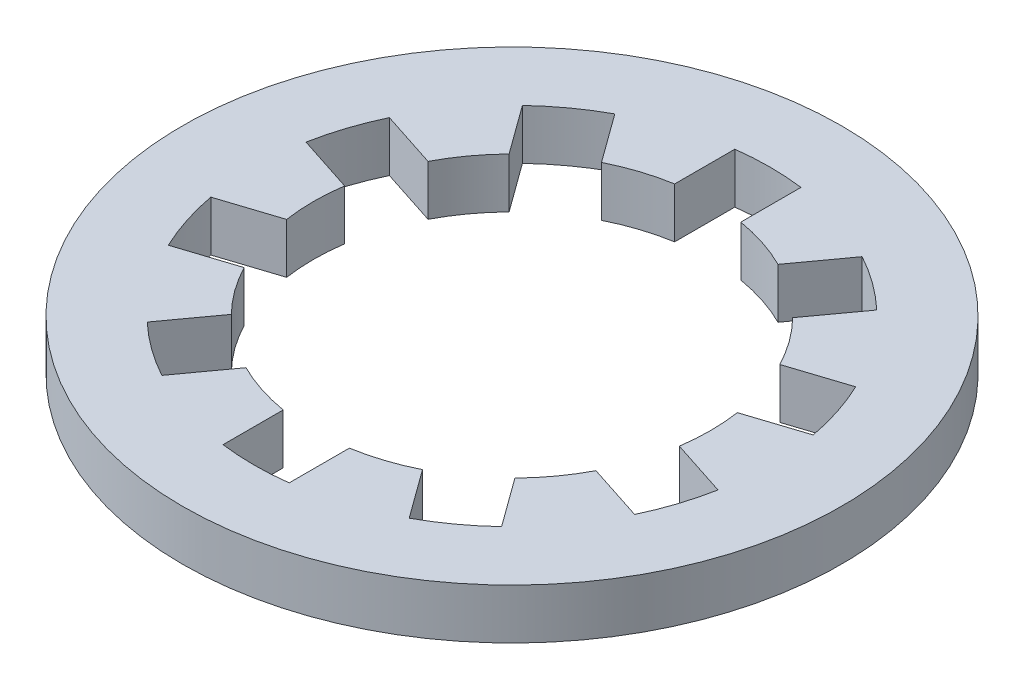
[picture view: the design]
ISO-10303-21;
HEADER;
FILE_DESCRIPTION(('STEP AP214'),'2;1');
FILE_NAME('part.step','',(''),(''),'','','');
FILE_SCHEMA(('AUTOMOTIVE_DESIGN { 1 0 10303 214 1 1 1 1 }'));
ENDSEC;
DATA;
#1=APPLICATION_CONTEXT('core data for automotive mechanical design processes');
#2=APPLICATION_PROTOCOL_DEFINITION('international standard','automotive_design',2000,#1);
#3=PRODUCT_CONTEXT('',#1,'mechanical');
#4=PRODUCT('Part','Part','',(#3));
#5=PRODUCT_RELATED_PRODUCT_CATEGORY('part','',(#4));
#6=PRODUCT_DEFINITION_FORMATION('','',#4);
#7=PRODUCT_DEFINITION_CONTEXT('part definition',#1,'design');
#8=PRODUCT_DEFINITION('design','',#6,#7);
#9=PRODUCT_DEFINITION_SHAPE('','',#8);
#10=(LENGTH_UNIT() NAMED_UNIT(*) SI_UNIT(.MILLI.,.METRE.));
#11=(NAMED_UNIT(*) PLANE_ANGLE_UNIT() SI_UNIT($,.RADIAN.));
#12=(NAMED_UNIT(*) SI_UNIT($,.STERADIAN.) SOLID_ANGLE_UNIT());
#13=UNCERTAINTY_MEASURE_WITH_UNIT(LENGTH_MEASURE(1.E-05),#10,'distance_accuracy_value','');
#14=(GEOMETRIC_REPRESENTATION_CONTEXT(3) GLOBAL_UNCERTAINTY_ASSIGNED_CONTEXT((#13)) GLOBAL_UNIT_ASSIGNED_CONTEXT((#10,
#11,#12)) REPRESENTATION_CONTEXT('',''));
#15=CARTESIAN_POINT('',(0.,0.,0.));
#16=DIRECTION('',(0.,0.,1.));
#17=DIRECTION('',(1.,0.,0.));
#18=AXIS2_PLACEMENT_3D('',#15,#16,#17);
#19=CARTESIAN_POINT('',(0.,1.7018,0.));
#20=DIRECTION('',(0.,-1.,0.));
#21=DIRECTION('',(0.,0.,-1.));
#22=AXIS2_PLACEMENT_3D('',#19,#20,#21);
#23=CYLINDRICAL_SURFACE('',#22,6.731);
#24=DIRECTION('',(0.,1.,0.));
#25=VECTOR('',#24,1.);
#26=CARTESIAN_POINT('',(-4.80862801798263,0.,4.70993180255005));
#27=LINE('',#26,#25);
#28=CARTESIAN_POINT('',(-4.80862801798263,0.,4.70993180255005));
#29=VERTEX_POINT('',#28);
#30=CARTESIAN_POINT('',(-4.80862801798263,1.7018,4.70993180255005));
#31=VERTEX_POINT('',#30);
#32=EDGE_CURVE('E322',#29,#31,#27,.T.);
#33=ORIENTED_EDGE('',*,*,#32,.F.);
#34=CARTESIAN_POINT('',(0.,0.,0.));
#35=DIRECTION('',(0.,1.,0.));
#36=DIRECTION('',(0.,0.,1.));
#37=AXIS2_PLACEMENT_3D('',#34,#35,#36);
#38=CIRCLE('',#37,6.731);
#39=CARTESIAN_POINT('',(-5.96535910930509,0.,3.11782804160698));
#40=VERTEX_POINT('',#39);
#41=EDGE_CURVE('E570',#40,#29,#38,.T.);
#42=ORIENTED_EDGE('',*,*,#41,.F.);
#43=DIRECTION('',(0.,1.,0.));
#44=VECTOR('',#43,1.);
#45=CARTESIAN_POINT('',(-5.96535910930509,0.,3.11782804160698));
#46=LINE('',#45,#44);
#47=CARTESIAN_POINT('',(-5.96535910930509,1.7018,3.11782804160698));
#48=VERTEX_POINT('',#47);
#49=EDGE_CURVE('E346',#40,#48,#46,.T.);
#50=ORIENTED_EDGE('',*,*,#49,.T.);
#51=CARTESIAN_POINT('',(0.,1.7018,0.));
#52=DIRECTION('',(0.,1.,0.));
#53=DIRECTION('',(0.,0.,1.));
#54=AXIS2_PLACEMENT_3D('',#51,#52,#53);
#55=CIRCLE('',#54,6.731);
#56=EDGE_CURVE('E567',#48,#31,#55,.T.);
#57=ORIENTED_EDGE('',*,*,#56,.T.);
#58=EDGE_LOOP('',(#33,#42,#50,#57));
#59=FACE_BOUND('',#58,.T.);
#60=ADVANCED_FACE('F35',(#59),#23,.F.);
#61=DIRECTION('',(0.,1.,0.));
#62=VECTOR('',#61,1.);
#63=CARTESIAN_POINT('',(-6.6586902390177,0.,0.983974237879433));
#64=LINE('',#63,#62);
#65=CARTESIAN_POINT('',(-6.6586902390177,0.,0.983974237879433));
#66=VERTEX_POINT('',#65);
#67=CARTESIAN_POINT('',(-6.6586902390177,1.7018,0.983974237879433));
#68=VERTEX_POINT('',#67);
#69=EDGE_CURVE('E344',#66,#68,#64,.T.);
#70=ORIENTED_EDGE('',*,*,#69,.F.);
#71=CARTESIAN_POINT('',(-6.65869023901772,0.,-0.983974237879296));
#72=VERTEX_POINT('',#71);
#73=EDGE_CURVE('E572',#72,#66,#38,.T.);
#74=ORIENTED_EDGE('',*,*,#73,.F.);
#75=DIRECTION('',(0.,1.,0.));
#76=VECTOR('',#75,1.);
#77=CARTESIAN_POINT('',(-6.65869023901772,0.,-0.983974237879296));
#78=LINE('',#77,#76);
#79=CARTESIAN_POINT('',(-6.65869023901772,1.7018,-0.983974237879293));
#80=VERTEX_POINT('',#79);
#81=EDGE_CURVE('E371',#72,#80,#78,.T.);
#82=ORIENTED_EDGE('',*,*,#81,.T.);
#83=EDGE_CURVE('E681',#80,#68,#55,.T.);
#84=ORIENTED_EDGE('',*,*,#83,.T.);
#85=EDGE_LOOP('',(#70,#74,#82,#84));
#86=FACE_BOUND('',#85,.T.);
#87=ADVANCED_FACE('F679',(#86),#23,.F.);
#88=DIRECTION('',(0.,1.,0.));
#89=VECTOR('',#88,1.);
#90=CARTESIAN_POINT('',(-5.96535910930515,0.,-3.11782804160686));
#91=LINE('',#90,#89);
#92=CARTESIAN_POINT('',(-5.96535910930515,0.,-3.11782804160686));
#93=VERTEX_POINT('',#92);
#94=CARTESIAN_POINT('',(-5.96535910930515,1.7018,-3.11782804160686));
#95=VERTEX_POINT('',#94);
#96=EDGE_CURVE('E369',#93,#95,#91,.T.);
#97=ORIENTED_EDGE('',*,*,#96,.F.);
#98=CARTESIAN_POINT('',(-4.80862801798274,0.,-4.70993180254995));
#99=VERTEX_POINT('',#98);
#100=EDGE_CURVE('E575',#99,#93,#38,.T.);
#101=ORIENTED_EDGE('',*,*,#100,.F.);
#102=DIRECTION('',(0.,1.,0.));
#103=VECTOR('',#102,1.);
#104=CARTESIAN_POINT('',(-4.80862801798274,0.,-4.70993180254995));
#105=LINE('',#104,#103);
#106=CARTESIAN_POINT('',(-4.80862801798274,1.7018,-4.70993180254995));
#107=VERTEX_POINT('',#106);
#108=EDGE_CURVE('E397',#99,#107,#105,.T.);
#109=ORIENTED_EDGE('',*,*,#108,.T.);
#110=EDGE_CURVE('E665',#107,#95,#55,.T.);
#111=ORIENTED_EDGE('',*,*,#110,.T.);
#112=EDGE_LOOP('',(#97,#101,#109,#111));
#113=FACE_BOUND('',#112,.T.);
#114=ADVANCED_FACE('F663',(#113),#23,.F.);
#115=DIRECTION('',(0.,1.,0.));
#116=VECTOR('',#115,1.);
#117=CARTESIAN_POINT('',(-2.99346355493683,0.,-6.02872598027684));
#118=LINE('',#117,#116);
#119=CARTESIAN_POINT('',(-2.99346355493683,0.,-6.02872598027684));
#120=VERTEX_POINT('',#119);
#121=CARTESIAN_POINT('',(-2.99346355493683,1.7018,-6.02872598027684));
#122=VERTEX_POINT('',#121);
#123=EDGE_CURVE('E395',#120,#122,#118,.T.);
#124=ORIENTED_EDGE('',*,*,#123,.F.);
#125=CARTESIAN_POINT('',(-1.12183333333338,0.,-6.63685550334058));
#126=VERTEX_POINT('',#125);
#127=EDGE_CURVE('E578',#126,#120,#38,.T.);
#128=ORIENTED_EDGE('',*,*,#127,.F.);
#129=DIRECTION('',(0.,1.,0.));
#130=VECTOR('',#129,1.);
#131=CARTESIAN_POINT('',(-1.12183333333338,0.,-6.63685550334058));
#132=LINE('',#131,#130);
#133=CARTESIAN_POINT('',(-1.12183333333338,1.7018,-6.63685550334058));
#134=VERTEX_POINT('',#133);
#135=EDGE_CURVE('E423',#126,#134,#132,.T.);
#136=ORIENTED_EDGE('',*,*,#135,.T.);
#137=EDGE_CURVE('E649',#134,#122,#55,.T.);
#138=ORIENTED_EDGE('',*,*,#137,.T.);
#139=EDGE_LOOP('',(#124,#128,#136,#138));
#140=FACE_BOUND('',#139,.T.);
#141=ADVANCED_FACE('F647',(#140),#23,.F.);
#142=DIRECTION('',(0.,1.,0.));
#143=VECTOR('',#142,1.);
#144=CARTESIAN_POINT('',(1.12183333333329,0.,-6.63685550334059));
#145=LINE('',#144,#143);
#146=CARTESIAN_POINT('',(1.12183333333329,0.,-6.63685550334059));
#147=VERTEX_POINT('',#146);
#148=CARTESIAN_POINT('',(1.12183333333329,1.7018,-6.63685550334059));
#149=VERTEX_POINT('',#148);
#150=EDGE_CURVE('E421',#147,#149,#145,.T.);
#151=ORIENTED_EDGE('',*,*,#150,.F.);
#152=CARTESIAN_POINT('',(2.99346355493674,0.,-6.02872598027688));
#153=VERTEX_POINT('',#152);
#154=EDGE_CURVE('E581',#153,#147,#38,.T.);
#155=ORIENTED_EDGE('',*,*,#154,.F.);
#156=DIRECTION('',(0.,1.,0.));
#157=VECTOR('',#156,1.);
#158=CARTESIAN_POINT('',(2.99346355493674,0.,-6.02872598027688));
#159=LINE('',#158,#157);
#160=CARTESIAN_POINT('',(2.99346355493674,1.7018,-6.02872598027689));
#161=VERTEX_POINT('',#160);
#162=EDGE_CURVE('E449',#153,#161,#159,.T.);
#163=ORIENTED_EDGE('',*,*,#162,.T.);
#164=EDGE_CURVE('E633',#161,#149,#55,.T.);
#165=ORIENTED_EDGE('',*,*,#164,.T.);
#166=EDGE_LOOP('',(#151,#155,#163,#165));
#167=FACE_BOUND('',#166,.T.);
#168=ADVANCED_FACE('F631',(#167),#23,.F.);
#169=DIRECTION('',(0.,1.,0.));
#170=VECTOR('',#169,1.);
#171=CARTESIAN_POINT('',(4.80862801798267,0.,-4.70993180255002));
#172=LINE('',#171,#170);
#173=CARTESIAN_POINT('',(4.80862801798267,0.,-4.70993180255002));
#174=VERTEX_POINT('',#173);
#175=CARTESIAN_POINT('',(4.80862801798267,1.7018,-4.70993180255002));
#176=VERTEX_POINT('',#175);
#177=EDGE_CURVE('E447',#174,#176,#172,.T.);
#178=ORIENTED_EDGE('',*,*,#177,.F.);
#179=CARTESIAN_POINT('',(5.96535910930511,0.,-3.11782804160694));
#180=VERTEX_POINT('',#179);
#181=EDGE_CURVE('E584',#180,#174,#38,.T.);
#182=ORIENTED_EDGE('',*,*,#181,.F.);
#183=DIRECTION('',(0.,1.,0.));
#184=VECTOR('',#183,1.);
#185=CARTESIAN_POINT('',(5.96535910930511,0.,-3.11782804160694));
#186=LINE('',#185,#184);
#187=CARTESIAN_POINT('',(5.96535910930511,1.7018,-3.11782804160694));
#188=VERTEX_POINT('',#187);
#189=EDGE_CURVE('E475',#180,#188,#186,.T.);
#190=ORIENTED_EDGE('',*,*,#189,.T.);
#191=EDGE_CURVE('E617',#188,#176,#55,.T.);
#192=ORIENTED_EDGE('',*,*,#191,.T.);
#193=EDGE_LOOP('',(#178,#182,#190,#192));
#194=FACE_BOUND('',#193,.T.);
#195=ADVANCED_FACE('F615',(#194),#23,.F.);
#196=DIRECTION('',(0.,1.,0.));
#197=VECTOR('',#196,1.);
#198=CARTESIAN_POINT('',(6.65869023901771,0.,-0.983974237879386));
#199=LINE('',#198,#197);
#200=CARTESIAN_POINT('',(6.65869023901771,0.,-0.983974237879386));
#201=VERTEX_POINT('',#200);
#202=CARTESIAN_POINT('',(6.65869023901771,1.7018,-0.983974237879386));
#203=VERTEX_POINT('',#202);
#204=EDGE_CURVE('E473',#201,#203,#199,.T.);
#205=ORIENTED_EDGE('',*,*,#204,.F.);
#206=CARTESIAN_POINT('',(6.65869023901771,0.,0.983974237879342));
#207=VERTEX_POINT('',#206);
#208=EDGE_CURVE('E569',#207,#201,#38,.T.);
#209=ORIENTED_EDGE('',*,*,#208,.F.);
#210=DIRECTION('',(0.,1.,0.));
#211=VECTOR('',#210,1.);
#212=CARTESIAN_POINT('',(6.65869023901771,0.,0.983974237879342));
#213=LINE('',#212,#211);
#214=CARTESIAN_POINT('',(6.65869023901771,1.7018,0.983974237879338));
#215=VERTEX_POINT('',#214);
#216=EDGE_CURVE('E501',#207,#215,#213,.T.);
#217=ORIENTED_EDGE('',*,*,#216,.T.);
#218=EDGE_CURVE('E596',#215,#203,#55,.T.);
#219=ORIENTED_EDGE('',*,*,#218,.T.);
#220=EDGE_LOOP('',(#205,#209,#217,#219));
#221=FACE_BOUND('',#220,.T.);
#222=ADVANCED_FACE('F593',(#221),#23,.F.);
#223=DIRECTION('',(0.,1.,0.));
#224=VECTOR('',#223,1.);
#225=CARTESIAN_POINT('',(5.96535910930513,0.,3.1178280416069));
#226=LINE('',#225,#224);
#227=CARTESIAN_POINT('',(5.96535910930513,0.,3.1178280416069));
#228=VERTEX_POINT('',#227);
#229=CARTESIAN_POINT('',(5.96535910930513,1.7018,3.1178280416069));
#230=VERTEX_POINT('',#229);
#231=EDGE_CURVE('E499',#228,#230,#226,.T.);
#232=ORIENTED_EDGE('',*,*,#231,.F.);
#233=CARTESIAN_POINT('',(4.8086280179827,0.,4.70993180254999));
#234=VERTEX_POINT('',#233);
#235=EDGE_CURVE('E565',#234,#228,#38,.T.);
#236=ORIENTED_EDGE('',*,*,#235,.F.);
#237=DIRECTION('',(0.,1.,0.));
#238=VECTOR('',#237,1.);
#239=CARTESIAN_POINT('',(4.8086280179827,0.,4.70993180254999));
#240=LINE('',#239,#238);
#241=CARTESIAN_POINT('',(4.8086280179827,1.7018,4.70993180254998));
#242=VERTEX_POINT('',#241);
#243=EDGE_CURVE('E527',#234,#242,#240,.T.);
#244=ORIENTED_EDGE('',*,*,#243,.T.);
#245=EDGE_CURVE('E561',#242,#230,#55,.T.);
#246=ORIENTED_EDGE('',*,*,#245,.T.);
#247=EDGE_LOOP('',(#232,#236,#244,#246));
#248=FACE_BOUND('',#247,.T.);
#249=ADVANCED_FACE('F731',(#248),#23,.F.);
#250=DIRECTION('',(0.,1.,0.));
#251=VECTOR('',#250,1.);
#252=CARTESIAN_POINT('',(2.99346355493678,0.,6.02872598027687));
#253=LINE('',#252,#251);
#254=CARTESIAN_POINT('',(2.99346355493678,0.,6.02872598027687));
#255=VERTEX_POINT('',#254);
#256=CARTESIAN_POINT('',(2.99346355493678,1.7018,6.02872598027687));
#257=VERTEX_POINT('',#256);
#258=EDGE_CURVE('E525',#255,#257,#253,.T.);
#259=ORIENTED_EDGE('',*,*,#258,.F.);
#260=CARTESIAN_POINT('',(1.12183333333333,0.,6.63685550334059));
#261=VERTEX_POINT('',#260);
#262=EDGE_CURVE('E563',#261,#255,#38,.T.);
#263=ORIENTED_EDGE('',*,*,#262,.F.);
#264=DIRECTION('',(0.,1.,0.));
#265=VECTOR('',#264,1.);
#266=CARTESIAN_POINT('',(1.12183333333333,0.,6.63685550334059));
#267=LINE('',#266,#265);
#268=CARTESIAN_POINT('',(1.12183333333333,1.7018,6.63685550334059));
#269=VERTEX_POINT('',#268);
#270=EDGE_CURVE('E554',#261,#269,#267,.T.);
#271=ORIENTED_EDGE('',*,*,#270,.T.);
#272=EDGE_CURVE('E558',#269,#257,#55,.T.);
#273=ORIENTED_EDGE('',*,*,#272,.T.);
#274=EDGE_LOOP('',(#259,#263,#271,#273));
#275=FACE_BOUND('',#274,.T.);
#276=ADVANCED_FACE('F714',(#275),#23,.F.);
#277=CARTESIAN_POINT('',(0.,1.7018,0.));
#278=DIRECTION('',(0.,1.,0.));
#279=DIRECTION('',(0.,0.,1.));
#280=AXIS2_PLACEMENT_3D('',#277,#278,#279);
#281=PLANE('',#280);
#282=DIRECTION('',(-0.587785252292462,0.,0.809016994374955));
#283=VECTOR('',#282,1.);
#284=CARTESIAN_POINT('',(-6.00843534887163,1.7018,6.36132492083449));
#285=LINE('',#284,#283);
#286=CARTESIAN_POINT('',(-6.00843534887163,1.7018,6.36132492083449));
#287=VERTEX_POINT('',#286);
#288=EDGE_CURVE('E311',#31,#287,#285,.T.);
#289=ORIENTED_EDGE('',*,*,#288,.F.);
#290=ORIENTED_EDGE('',*,*,#56,.F.);
#291=DIRECTION('',(0.95105651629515,0.,-0.309016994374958));
#292=VECTOR('',#291,1.);
#293=CARTESIAN_POINT('',(-7.9066881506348,1.7018,3.74860408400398));
#294=LINE('',#293,#292);
#295=CARTESIAN_POINT('',(-7.9066881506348,1.7018,3.74860408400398));
#296=VERTEX_POINT('',#295);
#297=EDGE_CURVE('E58',#296,#48,#294,.T.);
#298=ORIENTED_EDGE('',*,*,#297,.F.);
#299=CARTESIAN_POINT('',(0.,1.7018,0.));
#300=DIRECTION('',(0.,1.,0.));
#301=DIRECTION('',(-0.95105651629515,0.,0.309016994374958));
#302=AXIS2_PLACEMENT_3D('',#299,#300,#301);
#303=CIRCLE('',#302,8.7503);
#304=CARTESIAN_POINT('',(-8.60001928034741,1.7018,1.61475028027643));
#305=VERTEX_POINT('',#304);
#306=EDGE_CURVE('E321',#305,#296,#303,.T.);
#307=ORIENTED_EDGE('',*,*,#306,.F.);
#308=DIRECTION('',(-0.95105651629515,0.,0.309016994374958));
#309=VECTOR('',#308,1.);
#310=CARTESIAN_POINT('',(-8.60001928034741,1.7018,1.61475028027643));
#311=LINE('',#310,#309);
#312=EDGE_CURVE('E329',#68,#305,#311,.T.);
#313=ORIENTED_EDGE('',*,*,#312,.F.);
#314=ORIENTED_EDGE('',*,*,#83,.F.);
#315=DIRECTION('',(0.951056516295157,0.,0.309016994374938));
#316=VECTOR('',#315,1.);
#317=CARTESIAN_POINT('',(-8.60001928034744,1.7018,-1.61475028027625));
#318=LINE('',#317,#316);
#319=CARTESIAN_POINT('',(-8.60001928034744,1.7018,-1.61475028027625));
#320=VERTEX_POINT('',#319);
#321=EDGE_CURVE('E362',#320,#80,#318,.T.);
#322=ORIENTED_EDGE('',*,*,#321,.F.);
#323=CARTESIAN_POINT('',(0.,1.7018,0.));
#324=DIRECTION('',(0.,1.,0.));
#325=DIRECTION('',(-0.951056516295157,0.,-0.309016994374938));
#326=AXIS2_PLACEMENT_3D('',#323,#324,#325);
#327=CIRCLE('',#326,8.7503);
#328=CARTESIAN_POINT('',(-7.90668815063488,1.7018,-3.74860408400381));
#329=VERTEX_POINT('',#328);
#330=EDGE_CURVE('E343',#329,#320,#327,.T.);
#331=ORIENTED_EDGE('',*,*,#330,.F.);
#332=DIRECTION('',(-0.951056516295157,0.,-0.309016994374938));
#333=VECTOR('',#332,1.);
#334=CARTESIAN_POINT('',(-7.90668815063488,1.7018,-3.74860408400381));
#335=LINE('',#334,#333);
#336=EDGE_CURVE('E353',#95,#329,#335,.T.);
#337=ORIENTED_EDGE('',*,*,#336,.F.);
#338=ORIENTED_EDGE('',*,*,#110,.F.);
#339=DIRECTION('',(0.58778525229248,0.,0.809016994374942));
#340=VECTOR('',#339,1.);
#341=CARTESIAN_POINT('',(-6.00843534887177,1.7018,-6.36132492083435));
#342=LINE('',#341,#340);
#343=CARTESIAN_POINT('',(-6.00843534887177,1.7018,-6.36132492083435));
#344=VERTEX_POINT('',#343);
#345=EDGE_CURVE('E388',#344,#107,#342,.T.);
#346=ORIENTED_EDGE('',*,*,#345,.F.);
#347=CARTESIAN_POINT('',(0.,1.7018,0.));
#348=DIRECTION('',(0.,1.,0.));
#349=DIRECTION('',(-0.58778525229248,0.,-0.809016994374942));
#350=AXIS2_PLACEMENT_3D('',#347,#348,#349);
#351=CIRCLE('',#350,8.7503);
#352=CARTESIAN_POINT('',(-4.19327088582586,1.7018,-7.68011909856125));
#353=VERTEX_POINT('',#352);
#354=EDGE_CURVE('E368',#353,#344,#351,.T.);
#355=ORIENTED_EDGE('',*,*,#354,.F.);
#356=DIRECTION('',(-0.58778525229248,0.,-0.809016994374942));
#357=VECTOR('',#356,1.);
#358=CARTESIAN_POINT('',(-4.19327088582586,1.7018,-7.68011909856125));
#359=LINE('',#358,#357);
#360=EDGE_CURVE('E379',#122,#353,#359,.T.);
#361=ORIENTED_EDGE('',*,*,#360,.F.);
#362=ORIENTED_EDGE('',*,*,#137,.F.);
#363=DIRECTION('',(0.,0.,1.));
#364=VECTOR('',#363,1.);
#365=CARTESIAN_POINT('',(-1.12183333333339,1.7018,-8.67808965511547));
#366=LINE('',#365,#364);
#367=CARTESIAN_POINT('',(-1.12183333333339,1.7018,-8.67808965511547));
#368=VERTEX_POINT('',#367);
#369=EDGE_CURVE('E414',#368,#134,#366,.T.);
#370=ORIENTED_EDGE('',*,*,#369,.F.);
#371=CARTESIAN_POINT('',(0.,1.7018,0.));
#372=DIRECTION('',(0.,1.,0.));
#373=DIRECTION('',(0.,0.,-1.));
#374=AXIS2_PLACEMENT_3D('',#371,#372,#373);
#375=CIRCLE('',#374,8.7503);
#376=CARTESIAN_POINT('',(1.12183333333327,1.7018,-8.67808965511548));
#377=VERTEX_POINT('',#376);
#378=EDGE_CURVE('E394',#377,#368,#375,.T.);
#379=ORIENTED_EDGE('',*,*,#378,.F.);
#380=DIRECTION('',(0.,0.,-1.));
#381=VECTOR('',#380,1.);
#382=CARTESIAN_POINT('',(1.12183333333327,1.7018,-8.67808965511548));
#383=LINE('',#382,#381);
#384=EDGE_CURVE('E405',#149,#377,#383,.T.);
#385=ORIENTED_EDGE('',*,*,#384,.F.);
#386=ORIENTED_EDGE('',*,*,#164,.F.);
#387=DIRECTION('',(-0.587785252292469,0.,0.809016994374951));
#388=VECTOR('',#387,1.);
#389=CARTESIAN_POINT('',(4.19327088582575,1.7018,-7.68011909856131));
#390=LINE('',#389,#388);
#391=CARTESIAN_POINT('',(4.19327088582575,1.7018,-7.68011909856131));
#392=VERTEX_POINT('',#391);
#393=EDGE_CURVE('E440',#392,#161,#390,.T.);
#394=ORIENTED_EDGE('',*,*,#393,.F.);
#395=CARTESIAN_POINT('',(0.,1.7018,0.));
#396=DIRECTION('',(0.,1.,0.));
#397=DIRECTION('',(0.587785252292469,0.,-0.809016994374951));
#398=AXIS2_PLACEMENT_3D('',#395,#396,#397);
#399=CIRCLE('',#398,8.7503);
#400=CARTESIAN_POINT('',(6.00843534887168,1.7018,-6.36132492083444));
#401=VERTEX_POINT('',#400);
#402=EDGE_CURVE('E420',#401,#392,#399,.T.);
#403=ORIENTED_EDGE('',*,*,#402,.F.);
#404=DIRECTION('',(0.587785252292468,0.,-0.809016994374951));
#405=VECTOR('',#404,1.);
#406=CARTESIAN_POINT('',(6.00843534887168,1.7018,-6.36132492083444));
#407=LINE('',#406,#405);
#408=EDGE_CURVE('E431',#176,#401,#407,.T.);
#409=ORIENTED_EDGE('',*,*,#408,.F.);
#410=ORIENTED_EDGE('',*,*,#191,.F.);
#411=DIRECTION('',(-0.951056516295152,0.,0.309016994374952));
#412=VECTOR('',#411,1.);
#413=CARTESIAN_POINT('',(7.90668815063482,1.7018,-3.74860408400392));
#414=LINE('',#413,#412);
#415=CARTESIAN_POINT('',(7.90668815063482,1.7018,-3.74860408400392));
#416=VERTEX_POINT('',#415);
#417=EDGE_CURVE('E466',#416,#188,#414,.T.);
#418=ORIENTED_EDGE('',*,*,#417,.F.);
#419=CARTESIAN_POINT('',(0.,1.7018,0.));
#420=DIRECTION('',(0.,1.,0.));
#421=DIRECTION('',(0.951056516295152,0.,-0.309016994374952));
#422=AXIS2_PLACEMENT_3D('',#419,#420,#421);
#423=CIRCLE('',#422,8.7503);
#424=CARTESIAN_POINT('',(8.60001928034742,1.7018,-1.61475028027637));
#425=VERTEX_POINT('',#424);
#426=EDGE_CURVE('E446',#425,#416,#423,.T.);
#427=ORIENTED_EDGE('',*,*,#426,.F.);
#428=DIRECTION('',(0.951056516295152,0.,-0.309016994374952));
#429=VECTOR('',#428,1.);
#430=CARTESIAN_POINT('',(8.60001928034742,1.7018,-1.61475028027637));
#431=LINE('',#430,#429);
#432=EDGE_CURVE('E457',#203,#425,#431,.T.);
#433=ORIENTED_EDGE('',*,*,#432,.F.);
#434=ORIENTED_EDGE('',*,*,#218,.F.);
#435=DIRECTION('',(-0.951056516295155,0.,-0.309016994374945));
#436=VECTOR('',#435,1.);
#437=CARTESIAN_POINT('',(8.60001928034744,1.7018,1.6147502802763));
#438=LINE('',#437,#436);
#439=CARTESIAN_POINT('',(8.60001928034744,1.7018,1.6147502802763));
#440=VERTEX_POINT('',#439);
#441=EDGE_CURVE('E492',#440,#215,#438,.T.);
#442=ORIENTED_EDGE('',*,*,#441,.F.);
#443=CARTESIAN_POINT('',(0.,1.7018,0.));
#444=DIRECTION('',(0.,1.,0.));
#445=DIRECTION('',(0.951056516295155,0.,0.309016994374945));
#446=AXIS2_PLACEMENT_3D('',#443,#444,#445);
#447=CIRCLE('',#446,8.7503);
#448=CARTESIAN_POINT('',(7.90668815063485,1.7018,3.74860408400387));
#449=VERTEX_POINT('',#448);
#450=EDGE_CURVE('E472',#449,#440,#447,.T.);
#451=ORIENTED_EDGE('',*,*,#450,.F.);
#452=DIRECTION('',(0.951056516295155,0.,0.309016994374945));
#453=VECTOR('',#452,1.);
#454=CARTESIAN_POINT('',(7.90668815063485,1.7018,3.74860408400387));
#455=LINE('',#454,#453);
#456=EDGE_CURVE('E483',#230,#449,#455,.T.);
#457=ORIENTED_EDGE('',*,*,#456,.F.);
#458=ORIENTED_EDGE('',*,*,#245,.F.);
#459=DIRECTION('',(-0.587785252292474,0.,-0.809016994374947));
#460=VECTOR('',#459,1.);
#461=CARTESIAN_POINT('',(6.00843534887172,1.7018,6.3613249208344));
#462=LINE('',#461,#460);
#463=CARTESIAN_POINT('',(6.00843534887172,1.7018,6.3613249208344));
#464=VERTEX_POINT('',#463);
#465=EDGE_CURVE('E518',#464,#242,#462,.T.);
#466=ORIENTED_EDGE('',*,*,#465,.F.);
#467=CARTESIAN_POINT('',(0.,1.7018,0.));
#468=DIRECTION('',(0.,1.,0.));
#469=DIRECTION('',(0.587785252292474,0.,0.809016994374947));
#470=AXIS2_PLACEMENT_3D('',#467,#468,#469);
#471=CIRCLE('',#470,8.7503);
#472=CARTESIAN_POINT('',(4.1932708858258,1.7018,7.68011909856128));
#473=VERTEX_POINT('',#472);
#474=EDGE_CURVE('E498',#473,#464,#471,.T.);
#475=ORIENTED_EDGE('',*,*,#474,.F.);
#476=DIRECTION('',(0.587785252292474,0.,0.809016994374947));
#477=VECTOR('',#476,1.);
#478=CARTESIAN_POINT('',(4.1932708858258,1.7018,7.68011909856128));
#479=LINE('',#478,#477);
#480=EDGE_CURVE('E509',#257,#473,#479,.T.);
#481=ORIENTED_EDGE('',*,*,#480,.F.);
#482=ORIENTED_EDGE('',*,*,#272,.F.);
#483=DIRECTION('',(0.,0.,-1.));
#484=VECTOR('',#483,1.);
#485=CARTESIAN_POINT('',(1.12183333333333,1.7018,8.67808965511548));
#486=LINE('',#485,#484);
#487=CARTESIAN_POINT('',(1.12183333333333,1.7018,8.67808965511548));
#488=VERTEX_POINT('',#487);
#489=EDGE_CURVE('E544',#488,#269,#486,.T.);
#490=ORIENTED_EDGE('',*,*,#489,.F.);
#491=CARTESIAN_POINT('',(0.,1.7018,0.));
#492=DIRECTION('',(0.,1.,0.));
#493=DIRECTION('',(0.,0.,1.));
#494=AXIS2_PLACEMENT_3D('',#491,#492,#493);
#495=CIRCLE('',#494,8.7503);
#496=CARTESIAN_POINT('',(-1.12183333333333,1.7018,8.67808965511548));
#497=VERTEX_POINT('',#496);
#498=EDGE_CURVE('E524',#497,#488,#495,.T.);
#499=ORIENTED_EDGE('',*,*,#498,.F.);
#500=DIRECTION('',(0.,0.,1.));
#501=VECTOR('',#500,1.);
#502=CARTESIAN_POINT('',(-1.12183333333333,1.7018,8.67808965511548));
#503=LINE('',#502,#501);
#504=CARTESIAN_POINT('',(-1.12183333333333,1.7018,6.63685550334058));
#505=VERTEX_POINT('',#504);
#506=EDGE_CURVE('E535',#505,#497,#503,.T.);
#507=ORIENTED_EDGE('',*,*,#506,.F.);
#508=CARTESIAN_POINT('',(-2.99346355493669,1.7018,6.02872598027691));
#509=VERTEX_POINT('',#508);
#510=EDGE_CURVE('E562',#509,#505,#55,.T.);
#511=ORIENTED_EDGE('',*,*,#510,.F.);
#512=DIRECTION('',(0.587785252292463,0.,-0.809016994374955));
#513=VECTOR('',#512,1.);
#514=CARTESIAN_POINT('',(-4.19327088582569,1.7018,7.68011909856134));
#515=LINE('',#514,#513);
#516=CARTESIAN_POINT('',(-4.19327088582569,1.7018,7.68011909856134));
#517=VERTEX_POINT('',#516);
#518=EDGE_CURVE('E50',#517,#509,#515,.T.);
#519=ORIENTED_EDGE('',*,*,#518,.F.);
#520=CARTESIAN_POINT('',(0.,1.7018,0.));
#521=DIRECTION('',(0.,1.,0.));
#522=DIRECTION('',(-0.587785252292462,0.,0.809016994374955));
#523=AXIS2_PLACEMENT_3D('',#520,#521,#522);
#524=CIRCLE('',#523,8.7503);
#525=EDGE_CURVE('E299',#287,#517,#524,.T.);
#526=ORIENTED_EDGE('',*,*,#525,.F.);
#527=EDGE_LOOP('',(#289,#290,#298,#307,#313,#314,#322,#331,#337,#338,#346,#355,#361,#362,#370,
#379,#385,#386,#394,#403,#409,#410,#418,#427,#433,#434,#442,#451,#457,#458,#466,#475,#481,#482,
#490,#499,#507,#511,#519,#526));
#528=FACE_BOUND('',#527,.T.);
#529=CARTESIAN_POINT('',(0.,1.7018,0.));
#530=DIRECTION('',(0.,1.,0.));
#531=DIRECTION('',(0.,0.,1.));
#532=AXIS2_PLACEMENT_3D('',#529,#530,#531);
#533=CIRCLE('',#532,11.176);
#534=CARTESIAN_POINT('',(0.,1.7018,11.176));
#535=VERTEX_POINT('',#534);
#536=EDGE_CURVE('E11',#535,#535,#533,.T.);
#537=ORIENTED_EDGE('',*,*,#536,.T.);
#538=EDGE_LOOP('',(#537));
#539=FACE_BOUND('',#538,.T.);
#540=ADVANCED_FACE('F603',(#528,#539),#281,.T.);
#541=CARTESIAN_POINT('',(0.,0.,0.));
#542=DIRECTION('',(0.,1.,0.));
#543=DIRECTION('',(0.,0.,1.));
#544=AXIS2_PLACEMENT_3D('',#541,#542,#543);
#545=PLANE('',#544);
#546=CARTESIAN_POINT('',(0.,0.,0.));
#547=DIRECTION('',(0.,1.,0.));
#548=DIRECTION('',(0.,0.,1.));
#549=AXIS2_PLACEMENT_3D('',#546,#547,#548);
#550=CIRCLE('',#549,11.176);
#551=CARTESIAN_POINT('',(0.,0.,11.176));
#552=VERTEX_POINT('',#551);
#553=EDGE_CURVE('E39',#552,#552,#550,.T.);
#554=ORIENTED_EDGE('',*,*,#553,.F.);
#555=EDGE_LOOP('',(#554));
#556=FACE_BOUND('',#555,.T.);
#557=ORIENTED_EDGE('',*,*,#41,.T.);
#558=DIRECTION('',(-0.587785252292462,0.,0.809016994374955));
#559=VECTOR('',#558,1.);
#560=CARTESIAN_POINT('',(-6.00843534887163,0.,6.36132492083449));
#561=LINE('',#560,#559);
#562=CARTESIAN_POINT('',(-6.00843534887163,0.,6.36132492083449));
#563=VERTEX_POINT('',#562);
#564=EDGE_CURVE('E301',#29,#563,#561,.T.);
#565=ORIENTED_EDGE('',*,*,#564,.T.);
#566=CARTESIAN_POINT('',(0.,0.,0.));
#567=DIRECTION('',(0.,1.,0.));
#568=DIRECTION('',(-0.587785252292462,0.,0.809016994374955));
#569=AXIS2_PLACEMENT_3D('',#566,#567,#568);
#570=CIRCLE('',#569,8.7503);
#571=CARTESIAN_POINT('',(-4.19327088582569,0.,7.68011909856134));
#572=VERTEX_POINT('',#571);
#573=EDGE_CURVE('E296',#563,#572,#570,.T.);
#574=ORIENTED_EDGE('',*,*,#573,.T.);
#575=DIRECTION('',(0.587785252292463,0.,-0.809016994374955));
#576=VECTOR('',#575,1.);
#577=CARTESIAN_POINT('',(-4.19327088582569,0.,7.68011909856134));
#578=LINE('',#577,#576);
#579=CARTESIAN_POINT('',(-2.9934635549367,0.,6.02872598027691));
#580=VERTEX_POINT('',#579);
#581=EDGE_CURVE('E304',#572,#580,#578,.T.);
#582=ORIENTED_EDGE('',*,*,#581,.T.);
#583=CARTESIAN_POINT('',(-1.12183333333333,0.,6.63685550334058));
#584=VERTEX_POINT('',#583);
#585=EDGE_CURVE('E550',#580,#584,#38,.T.);
#586=ORIENTED_EDGE('',*,*,#585,.T.);
#587=DIRECTION('',(0.,0.,1.));
#588=VECTOR('',#587,1.);
#589=CARTESIAN_POINT('',(-1.12183333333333,0.,8.67808965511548));
#590=LINE('',#589,#588);
#591=CARTESIAN_POINT('',(-1.12183333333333,0.,8.67808965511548));
#592=VERTEX_POINT('',#591);
#593=EDGE_CURVE('E538',#584,#592,#590,.T.);
#594=ORIENTED_EDGE('',*,*,#593,.T.);
#595=CARTESIAN_POINT('',(0.,0.,0.));
#596=DIRECTION('',(0.,1.,0.));
#597=DIRECTION('',(0.,0.,1.));
#598=AXIS2_PLACEMENT_3D('',#595,#596,#597);
#599=CIRCLE('',#598,8.7503);
#600=CARTESIAN_POINT('',(1.12183333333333,0.,8.67808965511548));
#601=VERTEX_POINT('',#600);
#602=EDGE_CURVE('E531',#592,#601,#599,.T.);
#603=ORIENTED_EDGE('',*,*,#602,.T.);
#604=DIRECTION('',(0.,0.,-1.));
#605=VECTOR('',#604,1.);
#606=CARTESIAN_POINT('',(1.12183333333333,0.,8.67808965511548));
#607=LINE('',#606,#605);
#608=EDGE_CURVE('E534',#601,#261,#607,.T.);
#609=ORIENTED_EDGE('',*,*,#608,.T.);
#610=ORIENTED_EDGE('',*,*,#262,.T.);
#611=DIRECTION('',(0.587785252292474,0.,0.809016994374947));
#612=VECTOR('',#611,1.);
#613=CARTESIAN_POINT('',(4.1932708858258,0.,7.68011909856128));
#614=LINE('',#613,#612);
#615=CARTESIAN_POINT('',(4.1932708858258,0.,7.68011909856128));
#616=VERTEX_POINT('',#615);
#617=EDGE_CURVE('E512',#255,#616,#614,.T.);
#618=ORIENTED_EDGE('',*,*,#617,.T.);
#619=CARTESIAN_POINT('',(0.,0.,0.));
#620=DIRECTION('',(0.,1.,0.));
#621=DIRECTION('',(0.587785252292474,0.,0.809016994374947));
#622=AXIS2_PLACEMENT_3D('',#619,#620,#621);
#623=CIRCLE('',#622,8.7503);
#624=CARTESIAN_POINT('',(6.00843534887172,0.,6.3613249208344));
#625=VERTEX_POINT('',#624);
#626=EDGE_CURVE('E505',#616,#625,#623,.T.);
#627=ORIENTED_EDGE('',*,*,#626,.T.);
#628=DIRECTION('',(-0.587785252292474,0.,-0.809016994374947));
#629=VECTOR('',#628,1.);
#630=CARTESIAN_POINT('',(6.00843534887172,0.,6.3613249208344));
#631=LINE('',#630,#629);
#632=EDGE_CURVE('E508',#625,#234,#631,.T.);
#633=ORIENTED_EDGE('',*,*,#632,.T.);
#634=ORIENTED_EDGE('',*,*,#235,.T.);
#635=DIRECTION('',(0.951056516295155,0.,0.309016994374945));
#636=VECTOR('',#635,1.);
#637=CARTESIAN_POINT('',(7.90668815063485,0.,3.74860408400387));
#638=LINE('',#637,#636);
#639=CARTESIAN_POINT('',(7.90668815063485,0.,3.74860408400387));
#640=VERTEX_POINT('',#639);
#641=EDGE_CURVE('E486',#228,#640,#638,.T.);
#642=ORIENTED_EDGE('',*,*,#641,.T.);
#643=CARTESIAN_POINT('',(0.,0.,0.));
#644=DIRECTION('',(0.,1.,0.));
#645=DIRECTION('',(0.951056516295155,0.,0.309016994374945));
#646=AXIS2_PLACEMENT_3D('',#643,#644,#645);
#647=CIRCLE('',#646,8.7503);
#648=CARTESIAN_POINT('',(8.60001928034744,0.,1.6147502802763));
#649=VERTEX_POINT('',#648);
#650=EDGE_CURVE('E479',#640,#649,#647,.T.);
#651=ORIENTED_EDGE('',*,*,#650,.T.);
#652=DIRECTION('',(-0.951056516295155,0.,-0.309016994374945));
#653=VECTOR('',#652,1.);
#654=CARTESIAN_POINT('',(8.60001928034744,0.,1.6147502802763));
#655=LINE('',#654,#653);
#656=EDGE_CURVE('E482',#649,#207,#655,.T.);
#657=ORIENTED_EDGE('',*,*,#656,.T.);
#658=ORIENTED_EDGE('',*,*,#208,.T.);
#659=DIRECTION('',(0.951056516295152,0.,-0.309016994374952));
#660=VECTOR('',#659,1.);
#661=CARTESIAN_POINT('',(8.60001928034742,0.,-1.61475028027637));
#662=LINE('',#661,#660);
#663=CARTESIAN_POINT('',(8.60001928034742,0.,-1.61475028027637));
#664=VERTEX_POINT('',#663);
#665=EDGE_CURVE('E460',#201,#664,#662,.T.);
#666=ORIENTED_EDGE('',*,*,#665,.T.);
#667=CARTESIAN_POINT('',(0.,0.,0.));
#668=DIRECTION('',(0.,1.,0.));
#669=DIRECTION('',(0.951056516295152,0.,-0.309016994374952));
#670=AXIS2_PLACEMENT_3D('',#667,#668,#669);
#671=CIRCLE('',#670,8.7503);
#672=CARTESIAN_POINT('',(7.90668815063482,0.,-3.74860408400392));
#673=VERTEX_POINT('',#672);
#674=EDGE_CURVE('E453',#664,#673,#671,.T.);
#675=ORIENTED_EDGE('',*,*,#674,.T.);
#676=DIRECTION('',(-0.951056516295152,0.,0.309016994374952));
#677=VECTOR('',#676,1.);
#678=CARTESIAN_POINT('',(7.90668815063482,0.,-3.74860408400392));
#679=LINE('',#678,#677);
#680=EDGE_CURVE('E456',#673,#180,#679,.T.);
#681=ORIENTED_EDGE('',*,*,#680,.T.);
#682=ORIENTED_EDGE('',*,*,#181,.T.);
#683=DIRECTION('',(0.587785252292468,0.,-0.809016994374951));
#684=VECTOR('',#683,1.);
#685=CARTESIAN_POINT('',(6.00843534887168,0.,-6.36132492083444));
#686=LINE('',#685,#684);
#687=CARTESIAN_POINT('',(6.00843534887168,0.,-6.36132492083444));
#688=VERTEX_POINT('',#687);
#689=EDGE_CURVE('E434',#174,#688,#686,.T.);
#690=ORIENTED_EDGE('',*,*,#689,.T.);
#691=CARTESIAN_POINT('',(0.,0.,0.));
#692=DIRECTION('',(0.,1.,0.));
#693=DIRECTION('',(0.587785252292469,0.,-0.809016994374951));
#694=AXIS2_PLACEMENT_3D('',#691,#692,#693);
#695=CIRCLE('',#694,8.7503);
#696=CARTESIAN_POINT('',(4.19327088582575,0.,-7.68011909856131));
#697=VERTEX_POINT('',#696);
#698=EDGE_CURVE('E427',#688,#697,#695,.T.);
#699=ORIENTED_EDGE('',*,*,#698,.T.);
#700=DIRECTION('',(-0.587785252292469,0.,0.809016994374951));
#701=VECTOR('',#700,1.);
#702=CARTESIAN_POINT('',(4.19327088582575,0.,-7.68011909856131));
#703=LINE('',#702,#701);
#704=EDGE_CURVE('E430',#697,#153,#703,.T.);
#705=ORIENTED_EDGE('',*,*,#704,.T.);
#706=ORIENTED_EDGE('',*,*,#154,.T.);
#707=DIRECTION('',(0.,0.,-1.));
#708=VECTOR('',#707,1.);
#709=CARTESIAN_POINT('',(1.12183333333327,0.,-8.67808965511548));
#710=LINE('',#709,#708);
#711=CARTESIAN_POINT('',(1.12183333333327,0.,-8.67808965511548));
#712=VERTEX_POINT('',#711);
#713=EDGE_CURVE('E408',#147,#712,#710,.T.);
#714=ORIENTED_EDGE('',*,*,#713,.T.);
#715=CARTESIAN_POINT('',(0.,0.,0.));
#716=DIRECTION('',(0.,1.,0.));
#717=DIRECTION('',(0.,0.,-1.));
#718=AXIS2_PLACEMENT_3D('',#715,#716,#717);
#719=CIRCLE('',#718,8.7503);
#720=CARTESIAN_POINT('',(-1.12183333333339,0.,-8.67808965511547));
#721=VERTEX_POINT('',#720);
#722=EDGE_CURVE('E401',#712,#721,#719,.T.);
#723=ORIENTED_EDGE('',*,*,#722,.T.);
#724=DIRECTION('',(0.,0.,1.));
#725=VECTOR('',#724,1.);
#726=CARTESIAN_POINT('',(-1.12183333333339,0.,-8.67808965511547));
#727=LINE('',#726,#725);
#728=EDGE_CURVE('E404',#721,#126,#727,.T.);
#729=ORIENTED_EDGE('',*,*,#728,.T.);
#730=ORIENTED_EDGE('',*,*,#127,.T.);
#731=DIRECTION('',(-0.58778525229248,0.,-0.809016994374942));
#732=VECTOR('',#731,1.);
#733=CARTESIAN_POINT('',(-4.19327088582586,0.,-7.68011909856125));
#734=LINE('',#733,#732);
#735=CARTESIAN_POINT('',(-4.19327088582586,0.,-7.68011909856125));
#736=VERTEX_POINT('',#735);
#737=EDGE_CURVE('E382',#120,#736,#734,.T.);
#738=ORIENTED_EDGE('',*,*,#737,.T.);
#739=CARTESIAN_POINT('',(0.,0.,0.));
#740=DIRECTION('',(0.,1.,0.));
#741=DIRECTION('',(-0.58778525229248,0.,-0.809016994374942));
#742=AXIS2_PLACEMENT_3D('',#739,#740,#741);
#743=CIRCLE('',#742,8.7503);
#744=CARTESIAN_POINT('',(-6.00843534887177,0.,-6.36132492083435));
#745=VERTEX_POINT('',#744);
#746=EDGE_CURVE('E375',#736,#745,#743,.T.);
#747=ORIENTED_EDGE('',*,*,#746,.T.);
#748=DIRECTION('',(0.58778525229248,0.,0.809016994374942));
#749=VECTOR('',#748,1.);
#750=CARTESIAN_POINT('',(-6.00843534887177,0.,-6.36132492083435));
#751=LINE('',#750,#749);
#752=EDGE_CURVE('E378',#745,#99,#751,.T.);
#753=ORIENTED_EDGE('',*,*,#752,.T.);
#754=ORIENTED_EDGE('',*,*,#100,.T.);
#755=DIRECTION('',(-0.951056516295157,0.,-0.309016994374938));
#756=VECTOR('',#755,1.);
#757=CARTESIAN_POINT('',(-7.90668815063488,0.,-3.74860408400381));
#758=LINE('',#757,#756);
#759=CARTESIAN_POINT('',(-7.90668815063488,0.,-3.74860408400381));
#760=VERTEX_POINT('',#759);
#761=EDGE_CURVE('E356',#93,#760,#758,.T.);
#762=ORIENTED_EDGE('',*,*,#761,.T.);
#763=CARTESIAN_POINT('',(0.,0.,0.));
#764=DIRECTION('',(0.,1.,0.));
#765=DIRECTION('',(-0.951056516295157,0.,-0.309016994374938));
#766=AXIS2_PLACEMENT_3D('',#763,#764,#765);
#767=CIRCLE('',#766,8.7503);
#768=CARTESIAN_POINT('',(-8.60001928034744,0.,-1.61475028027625));
#769=VERTEX_POINT('',#768);
#770=EDGE_CURVE('E349',#760,#769,#767,.T.);
#771=ORIENTED_EDGE('',*,*,#770,.T.);
#772=DIRECTION('',(0.951056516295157,0.,0.309016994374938));
#773=VECTOR('',#772,1.);
#774=CARTESIAN_POINT('',(-8.60001928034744,0.,-1.61475028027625));
#775=LINE('',#774,#773);
#776=EDGE_CURVE('E352',#769,#72,#775,.T.);
#777=ORIENTED_EDGE('',*,*,#776,.T.);
#778=ORIENTED_EDGE('',*,*,#73,.T.);
#779=DIRECTION('',(-0.95105651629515,0.,0.309016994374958));
#780=VECTOR('',#779,1.);
#781=CARTESIAN_POINT('',(-8.60001928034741,0.,1.61475028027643));
#782=LINE('',#781,#780);
#783=CARTESIAN_POINT('',(-8.60001928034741,0.,1.61475028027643));
#784=VERTEX_POINT('',#783);
#785=EDGE_CURVE('E332',#66,#784,#782,.T.);
#786=ORIENTED_EDGE('',*,*,#785,.T.);
#787=CARTESIAN_POINT('',(0.,0.,0.));
#788=DIRECTION('',(0.,1.,0.));
#789=DIRECTION('',(-0.95105651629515,0.,0.309016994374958));
#790=AXIS2_PLACEMENT_3D('',#787,#788,#789);
#791=CIRCLE('',#790,8.7503);
#792=CARTESIAN_POINT('',(-7.9066881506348,0.,3.74860408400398));
#793=VERTEX_POINT('',#792);
#794=EDGE_CURVE('E325',#784,#793,#791,.T.);
#795=ORIENTED_EDGE('',*,*,#794,.T.);
#796=DIRECTION('',(0.95105651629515,0.,-0.309016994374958));
#797=VECTOR('',#796,1.);
#798=CARTESIAN_POINT('',(-7.9066881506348,0.,3.74860408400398));
#799=LINE('',#798,#797);
#800=EDGE_CURVE('E328',#793,#40,#799,.T.);
#801=ORIENTED_EDGE('',*,*,#800,.T.);
#802=EDGE_LOOP('',(#557,#565,#574,#582,#586,#594,#603,#609,#610,#618,#627,#633,#634,#642,#651,
#657,#658,#666,#675,#681,#682,#690,#699,#705,#706,#714,#723,#729,#730,#738,#747,#753,#754,#762,
#771,#777,#778,#786,#795,#801));
#803=FACE_BOUND('',#802,.T.);
#804=ADVANCED_FACE('F310',(#556,#803),#545,.F.);
#805=CARTESIAN_POINT('',(0.,1.7018,0.));
#806=DIRECTION('',(0.,-1.,0.));
#807=DIRECTION('',(0.,0.,-1.));
#808=AXIS2_PLACEMENT_3D('',#805,#806,#807);
#809=CYLINDRICAL_SURFACE('',#808,11.176);
#810=ORIENTED_EDGE('',*,*,#536,.F.);
#811=EDGE_LOOP('',(#810));
#812=FACE_BOUND('',#811,.T.);
#813=ORIENTED_EDGE('',*,*,#553,.T.);
#814=EDGE_LOOP('',(#813));
#815=FACE_BOUND('',#814,.T.);
#816=ADVANCED_FACE('F37',(#812,#815),#809,.T.);
#817=DIRECTION('',(0.,1.,0.));
#818=VECTOR('',#817,1.);
#819=CARTESIAN_POINT('',(-2.9934635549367,0.,6.02872598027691));
#820=LINE('',#819,#818);
#821=EDGE_CURVE('E300',#580,#509,#820,.T.);
#822=ORIENTED_EDGE('',*,*,#821,.T.);
#823=ORIENTED_EDGE('',*,*,#510,.T.);
#824=DIRECTION('',(0.,1.,0.));
#825=VECTOR('',#824,1.);
#826=CARTESIAN_POINT('',(-1.12183333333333,0.,6.63685550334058));
#827=LINE('',#826,#825);
#828=EDGE_CURVE('E551',#584,#505,#827,.T.);
#829=ORIENTED_EDGE('',*,*,#828,.F.);
#830=ORIENTED_EDGE('',*,*,#585,.F.);
#831=EDGE_LOOP('',(#822,#823,#829,#830));
#832=FACE_BOUND('',#831,.T.);
#833=ADVANCED_FACE('F701',(#832),#23,.F.);
#834=CARTESIAN_POINT('',(0.,0.,0.));
#835=DIRECTION('',(0.,1.,0.));
#836=DIRECTION('',(0.,0.,1.));
#837=AXIS2_PLACEMENT_3D('',#834,#835,#836);
#838=CYLINDRICAL_SURFACE('',#837,8.7503);
#839=ORIENTED_EDGE('',*,*,#498,.T.);
#840=DIRECTION('',(0.,1.,0.));
#841=VECTOR('',#840,1.);
#842=CARTESIAN_POINT('',(1.12183333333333,0.,8.67808965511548));
#843=LINE('',#842,#841);
#844=EDGE_CURVE('E541',#601,#488,#843,.T.);
#845=ORIENTED_EDGE('',*,*,#844,.F.);
#846=ORIENTED_EDGE('',*,*,#602,.F.);
#847=DIRECTION('',(0.,1.,0.));
#848=VECTOR('',#847,1.);
#849=CARTESIAN_POINT('',(-1.12183333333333,0.,8.67808965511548));
#850=LINE('',#849,#848);
#851=EDGE_CURVE('E548',#592,#497,#850,.T.);
#852=ORIENTED_EDGE('',*,*,#851,.T.);
#853=EDGE_LOOP('',(#839,#845,#846,#852));
#854=FACE_BOUND('',#853,.T.);
#855=ADVANCED_FACE('F707',(#854),#838,.F.);
#856=CARTESIAN_POINT('',(-1.12183333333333,0.,8.67808965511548));
#857=DIRECTION('',(-1.,0.,0.));
#858=DIRECTION('',(0.,0.,1.));
#859=AXIS2_PLACEMENT_3D('',#856,#857,#858);
#860=PLANE('',#859);
#861=ORIENTED_EDGE('',*,*,#506,.T.);
#862=ORIENTED_EDGE('',*,*,#851,.F.);
#863=ORIENTED_EDGE('',*,*,#593,.F.);
#864=ORIENTED_EDGE('',*,*,#828,.T.);
#865=EDGE_LOOP('',(#861,#862,#863,#864));
#866=FACE_BOUND('',#865,.T.);
#867=ADVANCED_FACE('F703',(#866),#860,.F.);
#868=CARTESIAN_POINT('',(1.12183333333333,0.,8.67808965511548));
#869=DIRECTION('',(1.,0.,0.));
#870=DIRECTION('',(0.,0.,-1.));
#871=AXIS2_PLACEMENT_3D('',#868,#869,#870);
#872=PLANE('',#871);
#873=ORIENTED_EDGE('',*,*,#489,.T.);
#874=ORIENTED_EDGE('',*,*,#270,.F.);
#875=ORIENTED_EDGE('',*,*,#608,.F.);
#876=ORIENTED_EDGE('',*,*,#844,.T.);
#877=EDGE_LOOP('',(#873,#874,#875,#876));
#878=FACE_BOUND('',#877,.T.);
#879=ADVANCED_FACE('F710',(#878),#872,.F.);
#880=CARTESIAN_POINT('',(0.,0.,0.));
#881=DIRECTION('',(0.,1.,0.));
#882=DIRECTION('',(0.,0.,1.));
#883=AXIS2_PLACEMENT_3D('',#880,#881,#882);
#884=CYLINDRICAL_SURFACE('',#883,8.7503);
#885=ORIENTED_EDGE('',*,*,#474,.T.);
#886=DIRECTION('',(0.,1.,0.));
#887=VECTOR('',#886,1.);
#888=CARTESIAN_POINT('',(6.00843534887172,0.,6.3613249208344));
#889=LINE('',#888,#887);
#890=EDGE_CURVE('E515',#625,#464,#889,.T.);
#891=ORIENTED_EDGE('',*,*,#890,.F.);
#892=ORIENTED_EDGE('',*,*,#626,.F.);
#893=DIRECTION('',(0.,1.,0.));
#894=VECTOR('',#893,1.);
#895=CARTESIAN_POINT('',(4.1932708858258,0.,7.68011909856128));
#896=LINE('',#895,#894);
#897=EDGE_CURVE('E522',#616,#473,#896,.T.);
#898=ORIENTED_EDGE('',*,*,#897,.T.);
#899=EDGE_LOOP('',(#885,#891,#892,#898));
#900=FACE_BOUND('',#899,.T.);
#901=ADVANCED_FACE('F724',(#900),#884,.F.);
#902=CARTESIAN_POINT('',(4.1932708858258,0.,7.68011909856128));
#903=DIRECTION('',(-0.809016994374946,0.,0.587785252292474));
#904=DIRECTION('',(0.587785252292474,0.,0.809016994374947));
#905=AXIS2_PLACEMENT_3D('',#902,#903,#904);
#906=PLANE('',#905);
#907=ORIENTED_EDGE('',*,*,#480,.T.);
#908=ORIENTED_EDGE('',*,*,#897,.F.);
#909=ORIENTED_EDGE('',*,*,#617,.F.);
#910=ORIENTED_EDGE('',*,*,#258,.T.);
#911=EDGE_LOOP('',(#907,#908,#909,#910));
#912=FACE_BOUND('',#911,.T.);
#913=ADVANCED_FACE('F719',(#912),#906,.F.);
#914=CARTESIAN_POINT('',(6.00843534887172,0.,6.3613249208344));
#915=DIRECTION('',(0.809016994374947,0.,-0.587785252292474));
#916=DIRECTION('',(-0.587785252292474,0.,-0.809016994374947));
#917=AXIS2_PLACEMENT_3D('',#914,#915,#916);
#918=PLANE('',#917);
#919=ORIENTED_EDGE('',*,*,#465,.T.);
#920=ORIENTED_EDGE('',*,*,#243,.F.);
#921=ORIENTED_EDGE('',*,*,#632,.F.);
#922=ORIENTED_EDGE('',*,*,#890,.T.);
#923=EDGE_LOOP('',(#919,#920,#921,#922));
#924=FACE_BOUND('',#923,.T.);
#925=ADVANCED_FACE('F726',(#924),#918,.F.);
#926=CARTESIAN_POINT('',(0.,0.,0.));
#927=DIRECTION('',(0.,1.,0.));
#928=DIRECTION('',(0.,0.,1.));
#929=AXIS2_PLACEMENT_3D('',#926,#927,#928);
#930=CYLINDRICAL_SURFACE('',#929,8.7503);
#931=ORIENTED_EDGE('',*,*,#450,.T.);
#932=DIRECTION('',(0.,1.,0.));
#933=VECTOR('',#932,1.);
#934=CARTESIAN_POINT('',(8.60001928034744,0.,1.6147502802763));
#935=LINE('',#934,#933);
#936=EDGE_CURVE('E489',#649,#440,#935,.T.);
#937=ORIENTED_EDGE('',*,*,#936,.F.);
#938=ORIENTED_EDGE('',*,*,#650,.F.);
#939=DIRECTION('',(0.,1.,0.));
#940=VECTOR('',#939,1.);
#941=CARTESIAN_POINT('',(7.90668815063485,0.,3.74860408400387));
#942=LINE('',#941,#940);
#943=EDGE_CURVE('E496',#640,#449,#942,.T.);
#944=ORIENTED_EDGE('',*,*,#943,.T.);
#945=EDGE_LOOP('',(#931,#937,#938,#944));
#946=FACE_BOUND('',#945,.T.);
#947=ADVANCED_FACE('F738',(#946),#930,.F.);
#948=CARTESIAN_POINT('',(7.90668815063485,0.,3.74860408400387));
#949=DIRECTION('',(-0.309016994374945,0.,0.951056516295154));
#950=DIRECTION('',(0.951056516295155,0.,0.309016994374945));
#951=AXIS2_PLACEMENT_3D('',#948,#949,#950);
#952=PLANE('',#951);
#953=ORIENTED_EDGE('',*,*,#456,.T.);
#954=ORIENTED_EDGE('',*,*,#943,.F.);
#955=ORIENTED_EDGE('',*,*,#641,.F.);
#956=ORIENTED_EDGE('',*,*,#231,.T.);
#957=EDGE_LOOP('',(#953,#954,#955,#956));
#958=FACE_BOUND('',#957,.T.);
#959=ADVANCED_FACE('F735',(#958),#952,.F.);
#960=CARTESIAN_POINT('',(8.60001928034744,0.,1.6147502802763));
#961=DIRECTION('',(0.309016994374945,0.,-0.951056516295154));
#962=DIRECTION('',(-0.951056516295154,0.,-0.309016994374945));
#963=AXIS2_PLACEMENT_3D('',#960,#961,#962);
#964=PLANE('',#963);
#965=ORIENTED_EDGE('',*,*,#441,.T.);
#966=ORIENTED_EDGE('',*,*,#216,.F.);
#967=ORIENTED_EDGE('',*,*,#656,.F.);
#968=ORIENTED_EDGE('',*,*,#936,.T.);
#969=EDGE_LOOP('',(#965,#966,#967,#968));
#970=FACE_BOUND('',#969,.T.);
#971=ADVANCED_FACE('F740',(#970),#964,.F.);
#972=CARTESIAN_POINT('',(0.,0.,0.));
#973=DIRECTION('',(0.,1.,0.));
#974=DIRECTION('',(0.,0.,1.));
#975=AXIS2_PLACEMENT_3D('',#972,#973,#974);
#976=CYLINDRICAL_SURFACE('',#975,8.7503);
#977=ORIENTED_EDGE('',*,*,#426,.T.);
#978=DIRECTION('',(0.,1.,0.));
#979=VECTOR('',#978,1.);
#980=CARTESIAN_POINT('',(7.90668815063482,0.,-3.74860408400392));
#981=LINE('',#980,#979);
#982=EDGE_CURVE('E463',#673,#416,#981,.T.);
#983=ORIENTED_EDGE('',*,*,#982,.F.);
#984=ORIENTED_EDGE('',*,*,#674,.F.);
#985=DIRECTION('',(0.,1.,0.));
#986=VECTOR('',#985,1.);
#987=CARTESIAN_POINT('',(8.60001928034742,0.,-1.61475028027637));
#988=LINE('',#987,#986);
#989=EDGE_CURVE('E470',#664,#425,#988,.T.);
#990=ORIENTED_EDGE('',*,*,#989,.T.);
#991=EDGE_LOOP('',(#977,#983,#984,#990));
#992=FACE_BOUND('',#991,.T.);
#993=ADVANCED_FACE('F609',(#992),#976,.F.);
#994=CARTESIAN_POINT('',(8.60001928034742,0.,-1.61475028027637));
#995=DIRECTION('',(0.309016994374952,0.,0.951056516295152));
#996=DIRECTION('',(0.951056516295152,0.,-0.309016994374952));
#997=AXIS2_PLACEMENT_3D('',#994,#995,#996);
#998=PLANE('',#997);
#999=ORIENTED_EDGE('',*,*,#432,.T.);
#1000=ORIENTED_EDGE('',*,*,#989,.F.);
#1001=ORIENTED_EDGE('',*,*,#665,.F.);
#1002=ORIENTED_EDGE('',*,*,#204,.T.);
#1003=EDGE_LOOP('',(#999,#1000,#1001,#1002));
#1004=FACE_BOUND('',#1003,.T.);
#1005=ADVANCED_FACE('F599',(#1004),#998,.F.);
#1006=CARTESIAN_POINT('',(7.90668815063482,0.,-3.74860408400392));
#1007=DIRECTION('',(-0.309016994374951,0.,-0.951056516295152));
#1008=DIRECTION('',(-0.951056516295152,0.,0.309016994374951));
#1009=AXIS2_PLACEMENT_3D('',#1006,#1007,#1008);
#1010=PLANE('',#1009);
#1011=ORIENTED_EDGE('',*,*,#417,.T.);
#1012=ORIENTED_EDGE('',*,*,#189,.F.);
#1013=ORIENTED_EDGE('',*,*,#680,.F.);
#1014=ORIENTED_EDGE('',*,*,#982,.T.);
#1015=EDGE_LOOP('',(#1011,#1012,#1013,#1014));
#1016=FACE_BOUND('',#1015,.T.);
#1017=ADVANCED_FACE('F934',(#1016),#1010,.F.);
#1018=CARTESIAN_POINT('',(0.,0.,0.));
#1019=DIRECTION('',(0.,1.,0.));
#1020=DIRECTION('',(0.,0.,1.));
#1021=AXIS2_PLACEMENT_3D('',#1018,#1019,#1020);
#1022=CYLINDRICAL_SURFACE('',#1021,8.7503);
#1023=ORIENTED_EDGE('',*,*,#402,.T.);
#1024=DIRECTION('',(0.,1.,0.));
#1025=VECTOR('',#1024,1.);
#1026=CARTESIAN_POINT('',(4.19327088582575,0.,-7.68011909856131));
#1027=LINE('',#1026,#1025);
#1028=EDGE_CURVE('E437',#697,#392,#1027,.T.);
#1029=ORIENTED_EDGE('',*,*,#1028,.F.);
#1030=ORIENTED_EDGE('',*,*,#698,.F.);
#1031=DIRECTION('',(0.,1.,0.));
#1032=VECTOR('',#1031,1.);
#1033=CARTESIAN_POINT('',(6.00843534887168,0.,-6.36132492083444));
#1034=LINE('',#1033,#1032);
#1035=EDGE_CURVE('E444',#688,#401,#1034,.T.);
#1036=ORIENTED_EDGE('',*,*,#1035,.T.);
#1037=EDGE_LOOP('',(#1023,#1029,#1030,#1036));
#1038=FACE_BOUND('',#1037,.T.);
#1039=ADVANCED_FACE('F625',(#1038),#1022,.F.);
#1040=CARTESIAN_POINT('',(6.00843534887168,0.,-6.36132492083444));
#1041=DIRECTION('',(0.809016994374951,0.,0.587785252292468));
#1042=DIRECTION('',(0.587785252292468,0.,-0.809016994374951));
#1043=AXIS2_PLACEMENT_3D('',#1040,#1041,#1042);
#1044=PLANE('',#1043);
#1045=ORIENTED_EDGE('',*,*,#408,.T.);
#1046=ORIENTED_EDGE('',*,*,#1035,.F.);
#1047=ORIENTED_EDGE('',*,*,#689,.F.);
#1048=ORIENTED_EDGE('',*,*,#177,.T.);
#1049=EDGE_LOOP('',(#1045,#1046,#1047,#1048));
#1050=FACE_BOUND('',#1049,.T.);
#1051=ADVANCED_FACE('F620',(#1050),#1044,.F.);
#1052=CARTESIAN_POINT('',(4.19327088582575,0.,-7.68011909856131));
#1053=DIRECTION('',(-0.809016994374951,0.,-0.587785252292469));
#1054=DIRECTION('',(-0.587785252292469,0.,0.809016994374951));
#1055=AXIS2_PLACEMENT_3D('',#1052,#1053,#1054);
#1056=PLANE('',#1055);
#1057=ORIENTED_EDGE('',*,*,#393,.T.);
#1058=ORIENTED_EDGE('',*,*,#162,.F.);
#1059=ORIENTED_EDGE('',*,*,#704,.F.);
#1060=ORIENTED_EDGE('',*,*,#1028,.T.);
#1061=EDGE_LOOP('',(#1057,#1058,#1059,#1060));
#1062=FACE_BOUND('',#1061,.T.);
#1063=ADVANCED_FACE('F962',(#1062),#1056,.F.);
#1064=CARTESIAN_POINT('',(0.,0.,0.));
#1065=DIRECTION('',(0.,1.,0.));
#1066=DIRECTION('',(0.,0.,1.));
#1067=AXIS2_PLACEMENT_3D('',#1064,#1065,#1066);
#1068=CYLINDRICAL_SURFACE('',#1067,8.7503);
#1069=ORIENTED_EDGE('',*,*,#378,.T.);
#1070=DIRECTION('',(0.,1.,0.));
#1071=VECTOR('',#1070,1.);
#1072=CARTESIAN_POINT('',(-1.12183333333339,0.,-8.67808965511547));
#1073=LINE('',#1072,#1071);
#1074=EDGE_CURVE('E411',#721,#368,#1073,.T.);
#1075=ORIENTED_EDGE('',*,*,#1074,.F.);
#1076=ORIENTED_EDGE('',*,*,#722,.F.);
#1077=DIRECTION('',(0.,1.,0.));
#1078=VECTOR('',#1077,1.);
#1079=CARTESIAN_POINT('',(1.12183333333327,0.,-8.67808965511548));
#1080=LINE('',#1079,#1078);
#1081=EDGE_CURVE('E418',#712,#377,#1080,.T.);
#1082=ORIENTED_EDGE('',*,*,#1081,.T.);
#1083=EDGE_LOOP('',(#1069,#1075,#1076,#1082));
#1084=FACE_BOUND('',#1083,.T.);
#1085=ADVANCED_FACE('F641',(#1084),#1068,.F.);
#1086=CARTESIAN_POINT('',(1.12183333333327,0.,-8.67808965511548));
#1087=DIRECTION('',(1.,0.,0.));
#1088=DIRECTION('',(0.,0.,-1.));
#1089=AXIS2_PLACEMENT_3D('',#1086,#1087,#1088);
#1090=PLANE('',#1089);
#1091=ORIENTED_EDGE('',*,*,#384,.T.);
#1092=ORIENTED_EDGE('',*,*,#1081,.F.);
#1093=ORIENTED_EDGE('',*,*,#713,.F.);
#1094=ORIENTED_EDGE('',*,*,#150,.T.);
#1095=EDGE_LOOP('',(#1091,#1092,#1093,#1094));
#1096=FACE_BOUND('',#1095,.T.);
#1097=ADVANCED_FACE('F636',(#1096),#1090,.F.);
#1098=CARTESIAN_POINT('',(-1.12183333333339,0.,-8.67808965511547));
#1099=DIRECTION('',(-1.,0.,0.));
#1100=DIRECTION('',(0.,0.,1.));
#1101=AXIS2_PLACEMENT_3D('',#1098,#1099,#1100);
#1102=PLANE('',#1101);
#1103=ORIENTED_EDGE('',*,*,#369,.T.);
#1104=ORIENTED_EDGE('',*,*,#135,.F.);
#1105=ORIENTED_EDGE('',*,*,#728,.F.);
#1106=ORIENTED_EDGE('',*,*,#1074,.T.);
#1107=EDGE_LOOP('',(#1103,#1104,#1105,#1106));
#1108=FACE_BOUND('',#1107,.T.);
#1109=ADVANCED_FACE('F990',(#1108),#1102,.F.);
#1110=CARTESIAN_POINT('',(0.,0.,0.));
#1111=DIRECTION('',(0.,1.,0.));
#1112=DIRECTION('',(0.,0.,1.));
#1113=AXIS2_PLACEMENT_3D('',#1110,#1111,#1112);
#1114=CYLINDRICAL_SURFACE('',#1113,8.7503);
#1115=ORIENTED_EDGE('',*,*,#354,.T.);
#1116=DIRECTION('',(0.,1.,0.));
#1117=VECTOR('',#1116,1.);
#1118=CARTESIAN_POINT('',(-6.00843534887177,0.,-6.36132492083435));
#1119=LINE('',#1118,#1117);
#1120=EDGE_CURVE('E385',#745,#344,#1119,.T.);
#1121=ORIENTED_EDGE('',*,*,#1120,.F.);
#1122=ORIENTED_EDGE('',*,*,#746,.F.);
#1123=DIRECTION('',(0.,1.,0.));
#1124=VECTOR('',#1123,1.);
#1125=CARTESIAN_POINT('',(-4.19327088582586,0.,-7.68011909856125));
#1126=LINE('',#1125,#1124);
#1127=EDGE_CURVE('E392',#736,#353,#1126,.T.);
#1128=ORIENTED_EDGE('',*,*,#1127,.T.);
#1129=EDGE_LOOP('',(#1115,#1121,#1122,#1128));
#1130=FACE_BOUND('',#1129,.T.);
#1131=ADVANCED_FACE('F657',(#1130),#1114,.F.);
#1132=CARTESIAN_POINT('',(-4.19327088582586,0.,-7.68011909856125));
#1133=DIRECTION('',(0.809016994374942,0.,-0.58778525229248));
#1134=DIRECTION('',(-0.58778525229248,0.,-0.809016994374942));
#1135=AXIS2_PLACEMENT_3D('',#1132,#1133,#1134);
#1136=PLANE('',#1135);
#1137=ORIENTED_EDGE('',*,*,#360,.T.);
#1138=ORIENTED_EDGE('',*,*,#1127,.F.);
#1139=ORIENTED_EDGE('',*,*,#737,.F.);
#1140=ORIENTED_EDGE('',*,*,#123,.T.);
#1141=EDGE_LOOP('',(#1137,#1138,#1139,#1140));
#1142=FACE_BOUND('',#1141,.T.);
#1143=ADVANCED_FACE('F652',(#1142),#1136,.F.);
#1144=CARTESIAN_POINT('',(-6.00843534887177,0.,-6.36132492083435));
#1145=DIRECTION('',(-0.809016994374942,0.,0.58778525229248));
#1146=DIRECTION('',(0.58778525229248,0.,0.809016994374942));
#1147=AXIS2_PLACEMENT_3D('',#1144,#1145,#1146);
#1148=PLANE('',#1147);
#1149=ORIENTED_EDGE('',*,*,#345,.T.);
#1150=ORIENTED_EDGE('',*,*,#108,.F.);
#1151=ORIENTED_EDGE('',*,*,#752,.F.);
#1152=ORIENTED_EDGE('',*,*,#1120,.T.);
#1153=EDGE_LOOP('',(#1149,#1150,#1151,#1152));
#1154=FACE_BOUND('',#1153,.T.);
#1155=ADVANCED_FACE('F1018',(#1154),#1148,.F.);
#1156=CARTESIAN_POINT('',(0.,0.,0.));
#1157=DIRECTION('',(0.,1.,0.));
#1158=DIRECTION('',(0.,0.,1.));
#1159=AXIS2_PLACEMENT_3D('',#1156,#1157,#1158);
#1160=CYLINDRICAL_SURFACE('',#1159,8.7503);
#1161=ORIENTED_EDGE('',*,*,#330,.T.);
#1162=DIRECTION('',(0.,1.,0.));
#1163=VECTOR('',#1162,1.);
#1164=CARTESIAN_POINT('',(-8.60001928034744,0.,-1.61475028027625));
#1165=LINE('',#1164,#1163);
#1166=EDGE_CURVE('E359',#769,#320,#1165,.T.);
#1167=ORIENTED_EDGE('',*,*,#1166,.F.);
#1168=ORIENTED_EDGE('',*,*,#770,.F.);
#1169=DIRECTION('',(0.,1.,0.));
#1170=VECTOR('',#1169,1.);
#1171=CARTESIAN_POINT('',(-7.90668815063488,0.,-3.74860408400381));
#1172=LINE('',#1171,#1170);
#1173=EDGE_CURVE('E366',#760,#329,#1172,.T.);
#1174=ORIENTED_EDGE('',*,*,#1173,.T.);
#1175=EDGE_LOOP('',(#1161,#1167,#1168,#1174));
#1176=FACE_BOUND('',#1175,.T.);
#1177=ADVANCED_FACE('F673',(#1176),#1160,.F.);
#1178=CARTESIAN_POINT('',(-7.90668815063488,0.,-3.74860408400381));
#1179=DIRECTION('',(0.309016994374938,0.,-0.951056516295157));
#1180=DIRECTION('',(-0.951056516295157,0.,-0.309016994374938));
#1181=AXIS2_PLACEMENT_3D('',#1178,#1179,#1180);
#1182=PLANE('',#1181);
#1183=ORIENTED_EDGE('',*,*,#336,.T.);
#1184=ORIENTED_EDGE('',*,*,#1173,.F.);
#1185=ORIENTED_EDGE('',*,*,#761,.F.);
#1186=ORIENTED_EDGE('',*,*,#96,.T.);
#1187=EDGE_LOOP('',(#1183,#1184,#1185,#1186));
#1188=FACE_BOUND('',#1187,.T.);
#1189=ADVANCED_FACE('F668',(#1188),#1182,.F.);
#1190=CARTESIAN_POINT('',(-8.60001928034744,0.,-1.61475028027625));
#1191=DIRECTION('',(-0.309016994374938,0.,0.951056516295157));
#1192=DIRECTION('',(0.951056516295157,0.,0.309016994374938));
#1193=AXIS2_PLACEMENT_3D('',#1190,#1191,#1192);
#1194=PLANE('',#1193);
#1195=ORIENTED_EDGE('',*,*,#321,.T.);
#1196=ORIENTED_EDGE('',*,*,#81,.F.);
#1197=ORIENTED_EDGE('',*,*,#776,.F.);
#1198=ORIENTED_EDGE('',*,*,#1166,.T.);
#1199=EDGE_LOOP('',(#1195,#1196,#1197,#1198));
#1200=FACE_BOUND('',#1199,.T.);
#1201=ADVANCED_FACE('F1046',(#1200),#1194,.F.);
#1202=CARTESIAN_POINT('',(0.,0.,0.));
#1203=DIRECTION('',(0.,1.,0.));
#1204=DIRECTION('',(0.,0.,1.));
#1205=AXIS2_PLACEMENT_3D('',#1202,#1203,#1204);
#1206=CYLINDRICAL_SURFACE('',#1205,8.7503);
#1207=ORIENTED_EDGE('',*,*,#306,.T.);
#1208=DIRECTION('',(0.,1.,0.));
#1209=VECTOR('',#1208,1.);
#1210=CARTESIAN_POINT('',(-7.9066881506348,0.,3.74860408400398));
#1211=LINE('',#1210,#1209);
#1212=EDGE_CURVE('E335',#793,#296,#1211,.T.);
#1213=ORIENTED_EDGE('',*,*,#1212,.F.);
#1214=ORIENTED_EDGE('',*,*,#794,.F.);
#1215=DIRECTION('',(0.,1.,0.));
#1216=VECTOR('',#1215,1.);
#1217=CARTESIAN_POINT('',(-8.60001928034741,0.,1.61475028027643));
#1218=LINE('',#1217,#1216);
#1219=EDGE_CURVE('E341',#784,#305,#1218,.T.);
#1220=ORIENTED_EDGE('',*,*,#1219,.T.);
#1221=EDGE_LOOP('',(#1207,#1213,#1214,#1220));
#1222=FACE_BOUND('',#1221,.T.);
#1223=ADVANCED_FACE('F688',(#1222),#1206,.F.);
#1224=CARTESIAN_POINT('',(-8.60001928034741,0.,1.61475028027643));
#1225=DIRECTION('',(-0.309016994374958,0.,-0.95105651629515));
#1226=DIRECTION('',(-0.95105651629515,0.,0.309016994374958));
#1227=AXIS2_PLACEMENT_3D('',#1224,#1225,#1226);
#1228=PLANE('',#1227);
#1229=ORIENTED_EDGE('',*,*,#312,.T.);
#1230=ORIENTED_EDGE('',*,*,#1219,.F.);
#1231=ORIENTED_EDGE('',*,*,#785,.F.);
#1232=ORIENTED_EDGE('',*,*,#69,.T.);
#1233=EDGE_LOOP('',(#1229,#1230,#1231,#1232));
#1234=FACE_BOUND('',#1233,.T.);
#1235=ADVANCED_FACE('F684',(#1234),#1228,.F.);
#1236=CARTESIAN_POINT('',(-7.9066881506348,0.,3.74860408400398));
#1237=DIRECTION('',(0.309016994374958,0.,0.95105651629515));
#1238=DIRECTION('',(0.95105651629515,0.,-0.309016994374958));
#1239=AXIS2_PLACEMENT_3D('',#1236,#1237,#1238);
#1240=PLANE('',#1239);
#1241=ORIENTED_EDGE('',*,*,#297,.T.);
#1242=ORIENTED_EDGE('',*,*,#49,.F.);
#1243=ORIENTED_EDGE('',*,*,#800,.F.);
#1244=ORIENTED_EDGE('',*,*,#1212,.T.);
#1245=EDGE_LOOP('',(#1241,#1242,#1243,#1244));
#1246=FACE_BOUND('',#1245,.T.);
#1247=ADVANCED_FACE('F1074',(#1246),#1240,.F.);
#1248=CARTESIAN_POINT('',(0.,0.,0.));
#1249=DIRECTION('',(0.,1.,0.));
#1250=DIRECTION('',(0.,0.,1.));
#1251=AXIS2_PLACEMENT_3D('',#1248,#1249,#1250);
#1252=CYLINDRICAL_SURFACE('',#1251,8.7503);
#1253=ORIENTED_EDGE('',*,*,#525,.T.);
#1254=DIRECTION('',(0.,1.,0.));
#1255=VECTOR('',#1254,1.);
#1256=CARTESIAN_POINT('',(-4.19327088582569,0.,7.68011909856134));
#1257=LINE('',#1256,#1255);
#1258=EDGE_CURVE('E292',#572,#517,#1257,.T.);
#1259=ORIENTED_EDGE('',*,*,#1258,.F.);
#1260=ORIENTED_EDGE('',*,*,#573,.F.);
#1261=DIRECTION('',(0.,1.,0.));
#1262=VECTOR('',#1261,1.);
#1263=CARTESIAN_POINT('',(-6.00843534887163,0.,6.36132492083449));
#1264=LINE('',#1263,#1262);
#1265=EDGE_CURVE('E319',#563,#287,#1264,.T.);
#1266=ORIENTED_EDGE('',*,*,#1265,.T.);
#1267=EDGE_LOOP('',(#1253,#1259,#1260,#1266));
#1268=FACE_BOUND('',#1267,.T.);
#1269=ADVANCED_FACE('F294',(#1268),#1252,.F.);
#1270=CARTESIAN_POINT('',(-6.00843534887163,0.,6.36132492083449));
#1271=DIRECTION('',(-0.809016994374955,0.,-0.587785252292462));
#1272=DIRECTION('',(-0.587785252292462,0.,0.809016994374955));
#1273=AXIS2_PLACEMENT_3D('',#1270,#1271,#1272);
#1274=PLANE('',#1273);
#1275=ORIENTED_EDGE('',*,*,#288,.T.);
#1276=ORIENTED_EDGE('',*,*,#1265,.F.);
#1277=ORIENTED_EDGE('',*,*,#564,.F.);
#1278=ORIENTED_EDGE('',*,*,#32,.T.);
#1279=EDGE_LOOP('',(#1275,#1276,#1277,#1278));
#1280=FACE_BOUND('',#1279,.T.);
#1281=ADVANCED_FACE('F695',(#1280),#1274,.F.);
#1282=CARTESIAN_POINT('',(-4.19327088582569,0.,7.68011909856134));
#1283=DIRECTION('',(0.809016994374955,0.,0.587785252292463));
#1284=DIRECTION('',(0.587785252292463,0.,-0.809016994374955));
#1285=AXIS2_PLACEMENT_3D('',#1282,#1283,#1284);
#1286=PLANE('',#1285);
#1287=ORIENTED_EDGE('',*,*,#518,.T.);
#1288=ORIENTED_EDGE('',*,*,#821,.F.);
#1289=ORIENTED_EDGE('',*,*,#581,.F.);
#1290=ORIENTED_EDGE('',*,*,#1258,.T.);
#1291=EDGE_LOOP('',(#1287,#1288,#1289,#1290));
#1292=FACE_BOUND('',#1291,.T.);
#1293=ADVANCED_FACE('F305',(#1292),#1286,.F.);
#1294=CLOSED_SHELL('',(#60,#87,#114,#141,#168,#195,#222,#249,#276,#540,#804,#816,#833,#855,#867,
#879,#901,#913,#925,#947,#959,#971,#993,#1005,#1017,#1039,#1051,#1063,#1085,#1097,#1109,#1131,
#1143,#1155,#1177,#1189,#1201,#1223,#1235,#1247,#1269,#1281,#1293));
#1295=MANIFOLD_SOLID_BREP('B2',#1294);
#1296=ADVANCED_BREP_SHAPE_REPRESENTATION('',(#18,#1295),#14);
#1297=SHAPE_DEFINITION_REPRESENTATION(#9,#1296);
ENDSEC;
END-ISO-10303-21;
